VERSION 5.8 ;
BUSBITCHARS "[]" ;
DIVIDERCHAR "/" ;
CLEARANCEMEASURE EUCLIDEAN ;

SITE coresite_DH_P
    SIZE 0.0450 BY 0.2880 ;
    CLASS CORE ;
    SYMMETRY X Y ;
END coresite_DH_P

SITE coresite_DH_N
    SIZE 0.0450 BY 0.2880 ;
    CLASS CORE ;
    SYMMETRY X Y ;
END coresite_DH_N

SITE coresite
    SIZE 0.0450 BY 0.1440 ;
    CLASS CORE ;
    SYMMETRY X Y ;
END coresite

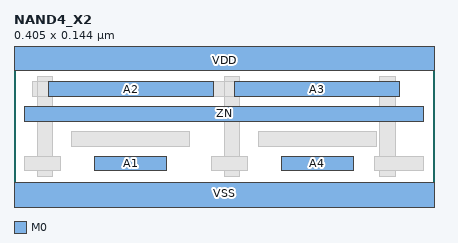
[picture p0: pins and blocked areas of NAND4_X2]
MACRO NAND4_X2
  CLASS CORE ;
  ORIGIN 0 0 ;
  FOREIGN NAND4_X2 0 0 ;
  SIZE 0.4050 BY 0.1440 ;
  SYMMETRY X Y ;
  SITE coresite ;
  PIN A1
    DIRECTION INPUT ;
    USE SIGNAL ;
    PORT
      LAYER M0 ;
        RECT 0.0780 0.0430 0.1470 0.0290 ;
    END
  END A1
  PIN A4
    DIRECTION INPUT ;
    USE SIGNAL ;
    PORT
      LAYER M0 ;
        RECT 0.2580 0.0430 0.3270 0.0290 ;
    END
  END A4
  PIN ZN
    DIRECTION OUTPUT ;
    USE SIGNAL ;
    PORT
      LAYER M0 ;
        RECT 0.0105 0.0910 0.3945 0.0770 ;
    END
  END ZN
  PIN A2
    DIRECTION INPUT ;
    USE SIGNAL ;
    PORT
      LAYER M0 ;
        RECT 0.0330 0.1150 0.1920 0.1010 ;
    END
  END A2
  PIN A3
    DIRECTION INPUT ;
    USE SIGNAL ;
    PORT
      LAYER M0 ;
        RECT 0.2130 0.1150 0.3720 0.1010 ;
    END
  END A3
  PIN VDD
    DIRECTION INOUT ;
    USE POWER ;
    SHAPE ABUTMENT ;
    PORT
      LAYER M0 ;
        RECT 0.0000 0.1260 0.4050 0.1620 ;
    END
  END VDD
  PIN VSS
    DIRECTION INOUT ;
    USE GROUND ;
    SHAPE ABUTMENT ;
    PORT
      LAYER M0 ;
        RECT 0.0000 -0.0180 0.4050 0.0180 ;
    END
  END VSS
  OBS
      LAYER V0 ;
        RECT 0.0230 0.0290 0.0370 0.0430 ;
        RECT 0.2030 0.0290 0.2170 0.0430 ;
        RECT 0.3530 0.0290 0.3670 0.0430 ;
      LAYER M1 ;
        RECT 0.0225 0.1200 0.0375 0.0240 ;
        RECT 0.2025 0.1200 0.2175 0.0240 ;
        RECT 0.3525 0.1200 0.3675 0.0240 ;
      LAYER M0 ;
        RECT 0.0105 0.0290 0.0450 0.0430 ;
        RECT 0.1905 0.0290 0.2250 0.0430 ;
        RECT 0.3480 0.0290 0.3945 0.0430 ;
        RECT 0.0555 0.0530 0.1695 0.0670 ;
        RECT 0.2355 0.0530 0.3495 0.0670 ;
      LAYER M2 ;
        RECT 0.0180 0.1010 0.3720 0.1150 ;
      LAYER V1 ;
        RECT 0.0230 0.1010 0.0370 0.1150 ;
        RECT 0.2030 0.1010 0.2170 0.1150 ;
        RECT 0.3530 0.1010 0.3670 0.1150 ;
  END
END NAND4_X2

END LIBRARY
